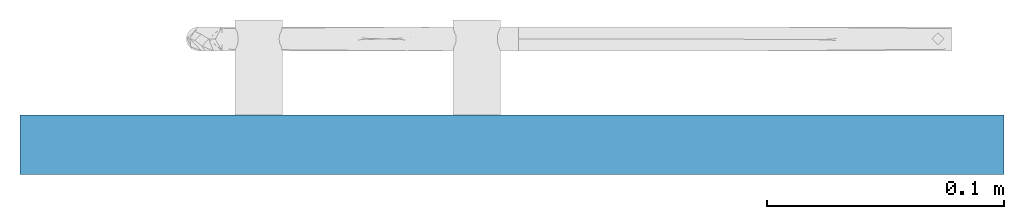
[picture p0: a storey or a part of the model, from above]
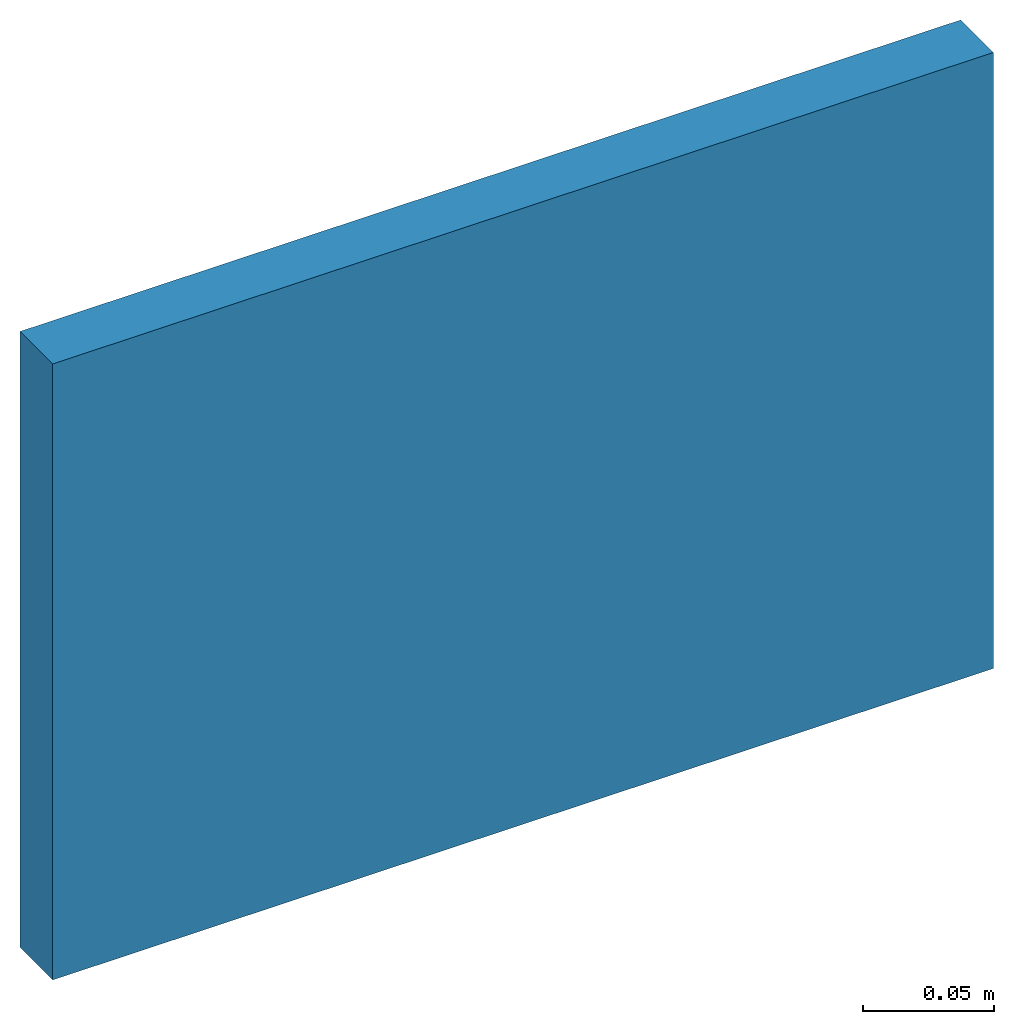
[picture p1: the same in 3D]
Properties of the parts of a building model (IFC2X3)

# File
Description: ViewDefinition [CoordinationView]
Time: 2016-05-16T12:15:18
Written by: The EXPRESS Data Manager Version 5.01.0100.02.64mod : 6 Jun 2012
Made in: 20140709_2115(x64) - Exporter 2014.0.2014.0709 - Default UI
Comment: STEP Physical File produced by: The EXPRESS Data Manager Version 5.01.0100.02.64mod : 6 Jun 2012 * Module: EDMstepFileFactory/EDMstandAlone * Creation date: Mon May 16 12:15:18 2016 * Host: BIM-HP * Database: C:\Users\dcole\AppData\Local\Temp\{6E7E7C95-552A-40E5-AC30-A1BCA4C2A4BB}\ifc * Database version: 5507 * Database creation date: Mon May 16 12:15:13 2016 * Schema: IFC2X3 * Model: DataRepository.ifc * Model creation date: Mon May 16 12:15:15 2016 * Header model: DataRepository.ifc_HeaderModel * Header model creation date: Mon May 16 12:15:15 2016 * EDMuser: sdai-user * EDMgroup: sdai-group * License ID and type: 5605 : Permanent license. Expiry date: * EDMstepFileFactory options: 020000

# IfcProject
LongName: P:\Fastrack\53721_BELL-CHEM\ADDITIONAL DRAWINGS 2016 BIM\IFC\BC270-2.ifc

# IfcSite, Default
RefLatitude: 42, 24, 53, 508911; RefLongitude: -71, -15, -29, -58837; RefElevation: 0 mm

# IfcBuilding
Pset_BuildingCommon - NumberOfStoreys: 1

# IfcBuildingStorey, Level 1
LongName: Level 1; Elevation: 0 mm
Constraints - Elevation Base: Project Base Point; Elevation: 0 mm
Dimensions - Computation Height: 0 mm
Identity Data - Building Story: yes; Structural: no; Name: Level 1
Graphics - Symbol at End 2 Default: yes; Color: 0; Line Pattern: -3000010; Symbol at End 1 Default: no; Line Weight: 1

# IfcBuildingElementProxy: BC 270-2 Dolphin Stainless Steel Toilet Roll Holder, BC 270-2:BC 270-2 Dolphin Stainless Steel Toilet Roll Holder:22976
In: Level 1
Material: Stainless Steel
Dimensions - Volume: 0.0000658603 m3; Projection: Diameter of toilet roll; Height: 85mm; Width: 323mm
Constraints - Level: Level: Level 1; Elevation: 86.6838 mm
Phasing - Phase Created: New Construction
Pset_ManufacturerTypeInformation - Manufacturer: Bell-Chem Products Co.
Pset_BuildingElementProxyCommon - Reference: BC 270-2 Dolphin Stainless Steel Toilet Roll Holder
Identity Data - Tel No.: +44 (0) 1424 202224; Assembly Code: D2010900; Email: info@dolphindispensers.co.uk; Model: BC 270-2; Description: Suface Mounted Toilet Roll Holder; Address line 1: Southpoint, Compass Park, Bodiam, Robertsbridge, TN32 5BS; Assembly Description: Other Plumbing Fixtures; Fax No.: +44 (0) 1424 205200; Manufacturer: Bell-Chem Products Co.; URL: www.dolphindispensers.co.uk
General - Product Page Link: http://www.dolphindispensers.co.uk/products/bc270-1-bc270-2-dolphin-stainless-steel-toilet-roll-holders/79.htm; Product Data: Contemporary design with two concealed fixings, High quality stainless steel, Holder diameter 10mm, Designed to hold 2 standard toilet rolls, Ideal for presigious office, hotel and residential projects

# IfcWallStandardCase: Basic Wall:Wall 1, Basic Wall:Wall 1:3092
In: Level 1
Type - PredefinedType: STANDARD; Material: Default Wall 25 mm
Type - Construction - Function: Exterior; Wrapping at Inserts: Do not wrap; Width: 25 mm
Type - Analytical Properties - Roughness: 1; Absorptance: 0.1
Type - Graphics - Coarse Scale Fill Color: 8454143
Dimensions - Area: 0.119254 m2; Volume: 0.00298136 m3; Length: 415 mm
Constraints - Location Line: Finish Face: Interior; Related to Mass: no; Base Constraint: Level: Level 1; Top is Attached: no; Base Extension Distance: 0 mm; Top Offset: 0 mm; Top Extension Distance: 0 mm; Base is Attached: no; Unconnected Height: 287.36 mm; Room Bounding: yes; Base Offset: -13.9001 mm
Structural - Enable Analytical Model: no; Structural Usage: Non-bearing; Structural: no
Phasing - Phase Created: New Construction
Pset_WallCommon - Reference: Wall 1; LoadBearing: no; ExtendToStructure: no; IsExternal: yes
